VERSION 5.8 ;
BUSBITCHARS "[]" ;
DIVIDERCHAR "/" ;
UNITS
    DATABASE MICRONS 1000 ;
END UNITS

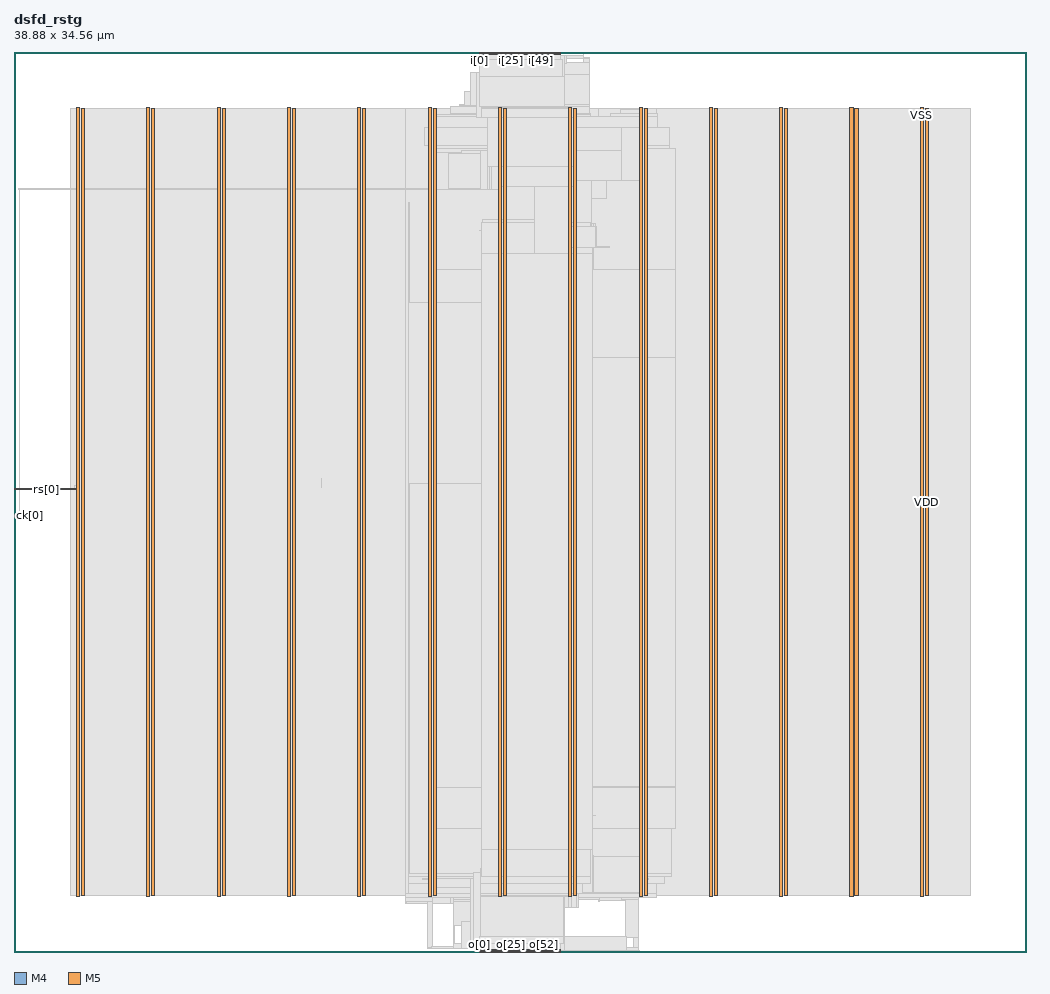
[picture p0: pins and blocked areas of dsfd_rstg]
MACRO dsfd_rstg
  FOREIGN dsfd_rstg 0 0 ;
  CLASS BLOCK ;
  SIZE 38.88 BY 34.56 ;
  PIN ck[0]
    DIRECTION INPUT ;
    USE SIGNAL ;
    PORT
      LAYER M4 ;
        RECT  0 16.752 0.084 16.776 ;
    END
    PORT
      LAYER M4 ;
        RECT  0.06 16.752 0.227 16.776 ;
    END
  END ck[0]
  PIN i[0]
    DIRECTION INPUT ;
    USE SIGNAL ;
    PORT
      LAYER M5 ;
        RECT  17.856 34.476 17.88 34.56 ;
    END
  END i[0]
  PIN i[10]
    DIRECTION INPUT ;
    USE SIGNAL ;
    PORT
      LAYER M5 ;
        RECT  18.336 34.476 18.36 34.56 ;
    END
  END i[10]
  PIN i[11]
    DIRECTION INPUT ;
    USE SIGNAL ;
    PORT
      LAYER M5 ;
        RECT  18.384 34.476 18.408 34.56 ;
    END
  END i[11]
  PIN i[12]
    DIRECTION INPUT ;
    USE SIGNAL ;
    PORT
      LAYER M5 ;
        RECT  18.432 34.476 18.456 34.56 ;
    END
  END i[12]
  PIN i[13]
    DIRECTION INPUT ;
    USE SIGNAL ;
    PORT
      LAYER M5 ;
        RECT  18.48 34.476 18.504 34.56 ;
    END
  END i[13]
  PIN i[14]
    DIRECTION INPUT ;
    USE SIGNAL ;
    PORT
      LAYER M5 ;
        RECT  18.528 34.476 18.552 34.56 ;
    END
  END i[14]
  PIN i[15]
    DIRECTION INPUT ;
    USE SIGNAL ;
    PORT
      LAYER M5 ;
        RECT  18.576 34.476 18.6 34.56 ;
    END
  END i[15]
  PIN i[16]
    DIRECTION INPUT ;
    USE SIGNAL ;
    PORT
      LAYER M5 ;
        RECT  18.624 34.476 18.648 34.56 ;
    END
  END i[16]
  PIN i[17]
    DIRECTION INPUT ;
    USE SIGNAL ;
    PORT
      LAYER M5 ;
        RECT  18.672 34.476 18.696 34.56 ;
    END
  END i[17]
  PIN i[18]
    DIRECTION INPUT ;
    USE SIGNAL ;
    PORT
      LAYER M5 ;
        RECT  18.72 34.476 18.744 34.56 ;
    END
  END i[18]
  PIN i[19]
    DIRECTION INPUT ;
    USE SIGNAL ;
    PORT
      LAYER M5 ;
        RECT  18.768 34.476 18.792 34.56 ;
    END
  END i[19]
  PIN i[1]
    DIRECTION INPUT ;
    USE SIGNAL ;
    PORT
      LAYER M5 ;
        RECT  17.904 34.476 17.928 34.56 ;
    END
  END i[1]
  PIN i[20]
    DIRECTION INPUT ;
    USE SIGNAL ;
    PORT
      LAYER M5 ;
        RECT  18.816 34.476 18.84 34.56 ;
    END
  END i[20]
  PIN i[21]
    DIRECTION INPUT ;
    USE SIGNAL ;
    PORT
      LAYER M5 ;
        RECT  18.864 34.476 18.888 34.56 ;
    END
  END i[21]
  PIN i[22]
    DIRECTION INPUT ;
    USE SIGNAL ;
    PORT
      LAYER M5 ;
        RECT  18.912 34.476 18.936 34.56 ;
    END
  END i[22]
  PIN i[23]
    DIRECTION INPUT ;
    USE SIGNAL ;
    PORT
      LAYER M5 ;
        RECT  18.96 34.476 18.984 34.56 ;
    END
  END i[23]
  PIN i[24]
    DIRECTION INPUT ;
    USE SIGNAL ;
    PORT
      LAYER M5 ;
        RECT  19.008 34.476 19.032 34.56 ;
    END
  END i[24]
  PIN i[25]
    DIRECTION INPUT ;
    USE SIGNAL ;
    PORT
      LAYER M5 ;
        RECT  19.056 34.476 19.08 34.56 ;
    END
  END i[25]
  PIN i[26]
    DIRECTION INPUT ;
    USE SIGNAL ;
    PORT
      LAYER M5 ;
        RECT  19.104 34.476 19.128 34.56 ;
    END
  END i[26]
  PIN i[27]
    DIRECTION INPUT ;
    USE SIGNAL ;
    PORT
      LAYER M5 ;
        RECT  19.152 34.476 19.176 34.56 ;
    END
  END i[27]
  PIN i[28]
    DIRECTION INPUT ;
    USE SIGNAL ;
    PORT
      LAYER M5 ;
        RECT  19.2 34.476 19.224 34.56 ;
    END
  END i[28]
  PIN i[29]
    DIRECTION INPUT ;
    USE SIGNAL ;
    PORT
      LAYER M5 ;
        RECT  19.248 34.476 19.272 34.56 ;
    END
  END i[29]
  PIN i[2]
    DIRECTION INPUT ;
    USE SIGNAL ;
    PORT
      LAYER M5 ;
        RECT  17.952 34.476 17.976 34.56 ;
    END
  END i[2]
  PIN i[30]
    DIRECTION INPUT ;
    USE SIGNAL ;
    PORT
      LAYER M5 ;
        RECT  19.296 34.476 19.32 34.56 ;
    END
  END i[30]
  PIN i[31]
    DIRECTION INPUT ;
    USE SIGNAL ;
    PORT
      LAYER M5 ;
        RECT  19.344 34.476 19.368 34.56 ;
    END
  END i[31]
  PIN i[32]
    DIRECTION INPUT ;
    USE SIGNAL ;
    PORT
      LAYER M5 ;
        RECT  19.392 34.476 19.416 34.56 ;
    END
  END i[32]
  PIN i[33]
    DIRECTION INPUT ;
    USE SIGNAL ;
    PORT
      LAYER M5 ;
        RECT  19.44 34.476 19.464 34.56 ;
    END
  END i[33]
  PIN i[34]
    DIRECTION INPUT ;
    USE SIGNAL ;
    PORT
      LAYER M5 ;
        RECT  19.488 34.476 19.512 34.56 ;
    END
  END i[34]
  PIN i[35]
    DIRECTION INPUT ;
    USE SIGNAL ;
    PORT
      LAYER M5 ;
        RECT  19.536 34.476 19.56 34.56 ;
    END
  END i[35]
  PIN i[36]
    DIRECTION INPUT ;
    USE SIGNAL ;
    PORT
      LAYER M5 ;
        RECT  19.584 34.476 19.608 34.56 ;
    END
  END i[36]
  PIN i[37]
    DIRECTION INPUT ;
    USE SIGNAL ;
    PORT
      LAYER M5 ;
        RECT  19.632 34.476 19.656 34.56 ;
    END
  END i[37]
  PIN i[38]
    DIRECTION INPUT ;
    USE SIGNAL ;
    PORT
      LAYER M5 ;
        RECT  19.68 34.476 19.704 34.56 ;
    END
  END i[38]
  PIN i[39]
    DIRECTION INPUT ;
    USE SIGNAL ;
    PORT
      LAYER M5 ;
        RECT  19.728 34.476 19.752 34.56 ;
    END
  END i[39]
  PIN i[3]
    DIRECTION INPUT ;
    USE SIGNAL ;
    PORT
      LAYER M5 ;
        RECT  18 34.476 18.024 34.56 ;
    END
  END i[3]
  PIN i[40]
    DIRECTION INPUT ;
    USE SIGNAL ;
    PORT
      LAYER M5 ;
        RECT  19.776 34.476 19.8 34.56 ;
    END
  END i[40]
  PIN i[41]
    DIRECTION INPUT ;
    USE SIGNAL ;
    PORT
      LAYER M5 ;
        RECT  19.824 34.476 19.848 34.56 ;
    END
  END i[41]
  PIN i[42]
    DIRECTION INPUT ;
    USE SIGNAL ;
    PORT
      LAYER M5 ;
        RECT  19.872 34.476 19.896 34.56 ;
    END
  END i[42]
  PIN i[43]
    DIRECTION INPUT ;
    USE SIGNAL ;
    PORT
      LAYER M5 ;
        RECT  19.92 34.476 19.944 34.56 ;
    END
  END i[43]
  PIN i[44]
    DIRECTION INPUT ;
    USE SIGNAL ;
    PORT
      LAYER M5 ;
        RECT  19.968 34.476 19.992 34.56 ;
    END
  END i[44]
  PIN i[45]
    DIRECTION INPUT ;
    USE SIGNAL ;
    PORT
      LAYER M5 ;
        RECT  20.016 34.476 20.04 34.56 ;
    END
  END i[45]
  PIN i[46]
    DIRECTION INPUT ;
    USE SIGNAL ;
    PORT
      LAYER M5 ;
        RECT  20.064 34.476 20.088 34.56 ;
    END
  END i[46]
  PIN i[47]
    DIRECTION INPUT ;
    USE SIGNAL ;
    PORT
      LAYER M5 ;
        RECT  20.112 34.476 20.136 34.56 ;
    END
  END i[47]
  PIN i[48]
    DIRECTION INPUT ;
    USE SIGNAL ;
    PORT
      LAYER M5 ;
        RECT  20.16 34.476 20.184 34.56 ;
    END
  END i[48]
  PIN i[49]
    DIRECTION INPUT ;
    USE SIGNAL ;
    PORT
      LAYER M5 ;
        RECT  20.208 34.476 20.232 34.56 ;
    END
  END i[49]
  PIN i[4]
    DIRECTION INPUT ;
    USE SIGNAL ;
    PORT
      LAYER M5 ;
        RECT  18.048 34.476 18.072 34.56 ;
    END
  END i[4]
  PIN i[50]
    DIRECTION INPUT ;
    USE SIGNAL ;
    PORT
      LAYER M5 ;
        RECT  20.256 34.476 20.28 34.56 ;
    END
  END i[50]
  PIN i[51]
    DIRECTION INPUT ;
    USE SIGNAL ;
    PORT
      LAYER M5 ;
        RECT  20.304 34.476 20.328 34.56 ;
    END
  END i[51]
  PIN i[52]
    DIRECTION INPUT ;
    USE SIGNAL ;
    PORT
      LAYER M5 ;
        RECT  20.352 34.476 20.376 34.56 ;
    END
  END i[52]
  PIN i[53]
    DIRECTION INPUT ;
    USE SIGNAL ;
    PORT
      LAYER M5 ;
        RECT  20.4 34.476 20.424 34.56 ;
    END
  END i[53]
  PIN i[54]
    DIRECTION INPUT ;
    USE SIGNAL ;
    PORT
      LAYER M5 ;
        RECT  20.448 34.476 20.472 34.56 ;
    END
  END i[54]
  PIN i[55]
    DIRECTION INPUT ;
    USE SIGNAL ;
    PORT
      LAYER M5 ;
        RECT  20.496 34.476 20.52 34.56 ;
    END
  END i[55]
  PIN i[56]
    DIRECTION INPUT ;
    USE SIGNAL ;
    PORT
      LAYER M5 ;
        RECT  20.544 34.476 20.568 34.56 ;
    END
  END i[56]
  PIN i[57]
    DIRECTION INPUT ;
    USE SIGNAL ;
    PORT
      LAYER M5 ;
        RECT  20.592 34.476 20.616 34.56 ;
    END
  END i[57]
  PIN i[58]
    DIRECTION INPUT ;
    USE SIGNAL ;
    PORT
      LAYER M5 ;
        RECT  20.64 34.476 20.664 34.56 ;
    END
  END i[58]
  PIN i[59]
    DIRECTION INPUT ;
    USE SIGNAL ;
    PORT
      LAYER M5 ;
        RECT  20.688 34.476 20.712 34.56 ;
    END
  END i[59]
  PIN i[5]
    DIRECTION INPUT ;
    USE SIGNAL ;
    PORT
      LAYER M5 ;
        RECT  18.096 34.476 18.12 34.56 ;
    END
  END i[5]
  PIN i[60]
    DIRECTION INPUT ;
    USE SIGNAL ;
    PORT
      LAYER M5 ;
        RECT  20.736 34.476 20.76 34.56 ;
    END
  END i[60]
  PIN i[61]
    DIRECTION INPUT ;
    USE SIGNAL ;
    PORT
      LAYER M5 ;
        RECT  20.784 34.476 20.808 34.56 ;
    END
  END i[61]
  PIN i[62]
    DIRECTION INPUT ;
    USE SIGNAL ;
    PORT
      LAYER M5 ;
        RECT  20.832 34.476 20.856 34.56 ;
    END
  END i[62]
  PIN i[63]
    DIRECTION INPUT ;
    USE SIGNAL ;
    PORT
      LAYER M5 ;
        RECT  20.88 34.476 20.904 34.56 ;
    END
  END i[63]
  PIN i[64]
    DIRECTION INPUT ;
    USE SIGNAL ;
    PORT
      LAYER M5 ;
        RECT  20.928 34.476 20.952 34.56 ;
    END
  END i[64]
  PIN i[65]
    DIRECTION INPUT ;
    USE SIGNAL ;
    PORT
      LAYER M5 ;
        RECT  20.976 34.476 21 34.56 ;
    END
  END i[65]
  PIN i[6]
    DIRECTION INPUT ;
    USE SIGNAL ;
    PORT
      LAYER M5 ;
        RECT  18.144 34.476 18.168 34.56 ;
    END
  END i[6]
  PIN i[7]
    DIRECTION INPUT ;
    USE SIGNAL ;
    PORT
      LAYER M5 ;
        RECT  18.192 34.476 18.216 34.56 ;
    END
  END i[7]
  PIN i[8]
    DIRECTION INPUT ;
    USE SIGNAL ;
    PORT
      LAYER M5 ;
        RECT  18.24 34.476 18.264 34.56 ;
    END
  END i[8]
  PIN i[9]
    DIRECTION INPUT ;
    USE SIGNAL ;
    PORT
      LAYER M5 ;
        RECT  18.288 34.476 18.312 34.56 ;
    END
  END i[9]
  PIN o[0]
    DIRECTION OUTPUT ;
    USE SIGNAL ;
    PORT
      LAYER M5 ;
        RECT  17.856 0 17.88 0.084 ;
    END
  END o[0]
  PIN o[10]
    DIRECTION OUTPUT ;
    USE SIGNAL ;
    PORT
      LAYER M5 ;
        RECT  18.336 0 18.36 0.084 ;
    END
  END o[10]
  PIN o[11]
    DIRECTION OUTPUT ;
    USE SIGNAL ;
    PORT
      LAYER M5 ;
        RECT  18.384 0 18.408 0.084 ;
    END
  END o[11]
  PIN o[12]
    DIRECTION OUTPUT ;
    USE SIGNAL ;
    PORT
      LAYER M5 ;
        RECT  18.432 0 18.456 0.084 ;
    END
  END o[12]
  PIN o[13]
    DIRECTION OUTPUT ;
    USE SIGNAL ;
    PORT
      LAYER M5 ;
        RECT  18.48 0 18.504 0.084 ;
    END
  END o[13]
  PIN o[14]
    DIRECTION OUTPUT ;
    USE SIGNAL ;
    PORT
      LAYER M5 ;
        RECT  18.528 0 18.552 0.084 ;
    END
  END o[14]
  PIN o[15]
    DIRECTION OUTPUT ;
    USE SIGNAL ;
    PORT
      LAYER M5 ;
        RECT  18.576 0 18.6 0.084 ;
    END
  END o[15]
  PIN o[16]
    DIRECTION OUTPUT ;
    USE SIGNAL ;
    PORT
      LAYER M5 ;
        RECT  18.624 0 18.648 0.084 ;
    END
  END o[16]
  PIN o[17]
    DIRECTION OUTPUT ;
    USE SIGNAL ;
    PORT
      LAYER M5 ;
        RECT  18.672 0 18.696 0.084 ;
    END
  END o[17]
  PIN o[18]
    DIRECTION OUTPUT ;
    USE SIGNAL ;
    PORT
      LAYER M5 ;
        RECT  18.72 0 18.744 0.084 ;
    END
  END o[18]
  PIN o[19]
    DIRECTION OUTPUT ;
    USE SIGNAL ;
    PORT
      LAYER M5 ;
        RECT  18.768 0 18.792 0.084 ;
    END
  END o[19]
  PIN o[1]
    DIRECTION OUTPUT ;
    USE SIGNAL ;
    PORT
      LAYER M5 ;
        RECT  17.904 0 17.928 0.084 ;
    END
  END o[1]
  PIN o[20]
    DIRECTION OUTPUT ;
    USE SIGNAL ;
    PORT
      LAYER M5 ;
        RECT  18.816 0 18.84 0.084 ;
    END
  END o[20]
  PIN o[21]
    DIRECTION OUTPUT ;
    USE SIGNAL ;
    PORT
      LAYER M5 ;
        RECT  18.864 0 18.888 0.084 ;
    END
  END o[21]
  PIN o[22]
    DIRECTION OUTPUT ;
    USE SIGNAL ;
    PORT
      LAYER M5 ;
        RECT  18.912 0 18.936 0.084 ;
    END
  END o[22]
  PIN o[23]
    DIRECTION OUTPUT ;
    USE SIGNAL ;
    PORT
      LAYER M5 ;
        RECT  18.96 0 18.984 0.084 ;
    END
  END o[23]
  PIN o[24]
    DIRECTION OUTPUT ;
    USE SIGNAL ;
    PORT
      LAYER M5 ;
        RECT  19.008 0 19.032 0.084 ;
    END
  END o[24]
  PIN o[25]
    DIRECTION OUTPUT ;
    USE SIGNAL ;
    PORT
      LAYER M5 ;
        RECT  19.056 0 19.08 0.084 ;
    END
  END o[25]
  PIN o[26]
    DIRECTION OUTPUT ;
    USE SIGNAL ;
    PORT
      LAYER M5 ;
        RECT  19.104 0 19.128 0.084 ;
    END
  END o[26]
  PIN o[27]
    DIRECTION OUTPUT ;
    USE SIGNAL ;
    PORT
      LAYER M5 ;
        RECT  19.152 0 19.176 0.084 ;
    END
  END o[27]
  PIN o[28]
    DIRECTION OUTPUT ;
    USE SIGNAL ;
    PORT
      LAYER M5 ;
        RECT  19.2 0 19.224 0.084 ;
    END
  END o[28]
  PIN o[29]
    DIRECTION OUTPUT ;
    USE SIGNAL ;
    PORT
      LAYER M5 ;
        RECT  19.248 0 19.272 0.084 ;
    END
  END o[29]
  PIN o[2]
    DIRECTION OUTPUT ;
    USE SIGNAL ;
    PORT
      LAYER M5 ;
        RECT  17.952 0 17.976 0.084 ;
    END
  END o[2]
  PIN o[30]
    DIRECTION OUTPUT ;
    USE SIGNAL ;
    PORT
      LAYER M5 ;
        RECT  19.296 0 19.32 0.084 ;
    END
  END o[30]
  PIN o[31]
    DIRECTION OUTPUT ;
    USE SIGNAL ;
    PORT
      LAYER M5 ;
        RECT  19.344 0 19.368 0.084 ;
    END
  END o[31]
  PIN o[32]
    DIRECTION OUTPUT ;
    USE SIGNAL ;
    PORT
      LAYER M5 ;
        RECT  19.392 0 19.416 0.084 ;
    END
  END o[32]
  PIN o[33]
    DIRECTION OUTPUT ;
    USE SIGNAL ;
    PORT
      LAYER M5 ;
        RECT  19.44 0 19.464 0.084 ;
    END
  END o[33]
  PIN o[34]
    DIRECTION OUTPUT ;
    USE SIGNAL ;
    PORT
      LAYER M5 ;
        RECT  19.488 0 19.512 0.084 ;
    END
  END o[34]
  PIN o[35]
    DIRECTION OUTPUT ;
    USE SIGNAL ;
    PORT
      LAYER M5 ;
        RECT  19.536 0 19.56 0.084 ;
    END
  END o[35]
  PIN o[36]
    DIRECTION OUTPUT ;
    USE SIGNAL ;
    PORT
      LAYER M5 ;
        RECT  19.584 0 19.608 0.084 ;
    END
  END o[36]
  PIN o[37]
    DIRECTION OUTPUT ;
    USE SIGNAL ;
    PORT
      LAYER M5 ;
        RECT  19.632 0 19.656 0.084 ;
    END
  END o[37]
  PIN o[38]
    DIRECTION OUTPUT ;
    USE SIGNAL ;
    PORT
      LAYER M5 ;
        RECT  19.68 0 19.704 0.084 ;
    END
  END o[38]
  PIN o[39]
    DIRECTION OUTPUT ;
    USE SIGNAL ;
    PORT
      LAYER M5 ;
        RECT  19.728 0 19.752 0.084 ;
    END
  END o[39]
  PIN o[3]
    DIRECTION OUTPUT ;
    USE SIGNAL ;
    PORT
      LAYER M5 ;
        RECT  18 0 18.024 0.084 ;
    END
  END o[3]
  PIN o[40]
    DIRECTION OUTPUT ;
    USE SIGNAL ;
    PORT
      LAYER M5 ;
        RECT  19.776 0 19.8 0.084 ;
    END
  END o[40]
  PIN o[41]
    DIRECTION OUTPUT ;
    USE SIGNAL ;
    PORT
      LAYER M5 ;
        RECT  19.824 0 19.848 0.084 ;
    END
  END o[41]
  PIN o[42]
    DIRECTION OUTPUT ;
    USE SIGNAL ;
    PORT
      LAYER M5 ;
        RECT  19.872 0 19.896 0.084 ;
    END
  END o[42]
  PIN o[43]
    DIRECTION OUTPUT ;
    USE SIGNAL ;
    PORT
      LAYER M5 ;
        RECT  19.92 0 19.944 0.084 ;
    END
  END o[43]
  PIN o[44]
    DIRECTION OUTPUT ;
    USE SIGNAL ;
    PORT
      LAYER M5 ;
        RECT  19.968 0 19.992 0.084 ;
    END
  END o[44]
  PIN o[45]
    DIRECTION OUTPUT ;
    USE SIGNAL ;
    PORT
      LAYER M5 ;
        RECT  20.016 0 20.04 0.084 ;
    END
  END o[45]
  PIN o[46]
    DIRECTION OUTPUT ;
    USE SIGNAL ;
    PORT
      LAYER M5 ;
        RECT  20.064 0 20.088 0.084 ;
    END
  END o[46]
  PIN o[47]
    DIRECTION OUTPUT ;
    USE SIGNAL ;
    PORT
      LAYER M5 ;
        RECT  20.112 0 20.136 0.084 ;
    END
  END o[47]
  PIN o[48]
    DIRECTION OUTPUT ;
    USE SIGNAL ;
    PORT
      LAYER M5 ;
        RECT  20.16 0 20.184 0.084 ;
    END
  END o[48]
  PIN o[49]
    DIRECTION OUTPUT ;
    USE SIGNAL ;
    PORT
      LAYER M5 ;
        RECT  20.208 0 20.232 0.084 ;
    END
  END o[49]
  PIN o[4]
    DIRECTION OUTPUT ;
    USE SIGNAL ;
    PORT
      LAYER M5 ;
        RECT  18.048 0 18.072 0.084 ;
    END
  END o[4]
  PIN o[50]
    DIRECTION OUTPUT ;
    USE SIGNAL ;
    PORT
      LAYER M5 ;
        RECT  20.256 0 20.28 0.084 ;
    END
  END o[50]
  PIN o[51]
    DIRECTION OUTPUT ;
    USE SIGNAL ;
    PORT
      LAYER M5 ;
        RECT  20.304 0 20.328 0.084 ;
    END
  END o[51]
  PIN o[52]
    DIRECTION OUTPUT ;
    USE SIGNAL ;
    PORT
      LAYER M5 ;
        RECT  20.352 0 20.376 0.084 ;
    END
  END o[52]
  PIN o[53]
    DIRECTION OUTPUT ;
    USE SIGNAL ;
    PORT
      LAYER M5 ;
        RECT  20.4 0 20.424 0.084 ;
    END
  END o[53]
  PIN o[54]
    DIRECTION OUTPUT ;
    USE SIGNAL ;
    PORT
      LAYER M5 ;
        RECT  20.448 0 20.472 0.084 ;
    END
  END o[54]
  PIN o[55]
    DIRECTION OUTPUT ;
    USE SIGNAL ;
    PORT
      LAYER M5 ;
        RECT  20.496 0 20.52 0.084 ;
    END
  END o[55]
  PIN o[56]
    DIRECTION OUTPUT ;
    USE SIGNAL ;
    PORT
      LAYER M5 ;
        RECT  20.544 0 20.568 0.084 ;
    END
  END o[56]
  PIN o[57]
    DIRECTION OUTPUT ;
    USE SIGNAL ;
    PORT
      LAYER M5 ;
        RECT  20.592 0 20.616 0.084 ;
    END
  END o[57]
  PIN o[58]
    DIRECTION OUTPUT ;
    USE SIGNAL ;
    PORT
      LAYER M5 ;
        RECT  20.64 0 20.664 0.084 ;
    END
  END o[58]
  PIN o[59]
    DIRECTION OUTPUT ;
    USE SIGNAL ;
    PORT
      LAYER M5 ;
        RECT  20.688 0 20.712 0.084 ;
    END
  END o[59]
  PIN o[5]
    DIRECTION OUTPUT ;
    USE SIGNAL ;
    PORT
      LAYER M5 ;
        RECT  18.096 0 18.12 0.084 ;
    END
  END o[5]
  PIN o[60]
    DIRECTION OUTPUT ;
    USE SIGNAL ;
    PORT
      LAYER M5 ;
        RECT  20.736 0 20.76 0.084 ;
    END
  END o[60]
  PIN o[61]
    DIRECTION OUTPUT ;
    USE SIGNAL ;
    PORT
      LAYER M5 ;
        RECT  20.784 0 20.808 0.084 ;
    END
  END o[61]
  PIN o[62]
    DIRECTION OUTPUT ;
    USE SIGNAL ;
    PORT
      LAYER M5 ;
        RECT  20.832 0 20.856 0.084 ;
    END
  END o[62]
  PIN o[63]
    DIRECTION OUTPUT ;
    USE SIGNAL ;
    PORT
      LAYER M5 ;
        RECT  20.88 0 20.904 0.084 ;
    END
  END o[63]
  PIN o[64]
    DIRECTION OUTPUT ;
    USE SIGNAL ;
    PORT
      LAYER M5 ;
        RECT  20.928 0 20.952 0.084 ;
    END
  END o[64]
  PIN o[65]
    DIRECTION OUTPUT ;
    USE SIGNAL ;
    PORT
      LAYER M5 ;
        RECT  20.976 0 21 0.084 ;
    END
  END o[65]
  PIN o[6]
    DIRECTION OUTPUT ;
    USE SIGNAL ;
    PORT
      LAYER M5 ;
        RECT  18.144 0 18.168 0.084 ;
    END
  END o[6]
  PIN o[7]
    DIRECTION OUTPUT ;
    USE SIGNAL ;
    PORT
      LAYER M5 ;
        RECT  18.192 0 18.216 0.084 ;
    END
  END o[7]
  PIN o[8]
    DIRECTION OUTPUT ;
    USE SIGNAL ;
    PORT
      LAYER M5 ;
        RECT  18.24 0 18.264 0.084 ;
    END
  END o[8]
  PIN o[9]
    DIRECTION OUTPUT ;
    USE SIGNAL ;
    PORT
      LAYER M5 ;
        RECT  18.288 0 18.312 0.084 ;
    END
  END o[9]
  PIN rs[0]
    DIRECTION INPUT ;
    USE SIGNAL ;
    PORT
      LAYER M4 ;
        RECT  0 17.76 0.084 17.784 ;
    END
    PORT
      LAYER M4 ;
        RECT  0.06 17.76 2.408 17.784 ;
    END
  END rs[0]
  PIN VDD
    DIRECTION INOUT ;
    USE POWER ;
    PORT
      LAYER M5 ;
        RECT  34.992 2.151 35.112 32.409 ;
        RECT  32.292 2.151 32.412 32.409 ;
        RECT  29.592 2.151 29.712 32.409 ;
        RECT  26.892 2.151 27.012 32.409 ;
        RECT  24.192 2.151 24.312 32.409 ;
        RECT  21.492 2.151 21.612 32.409 ;
        RECT  18.792 2.151 18.912 32.409 ;
        RECT  16.092 2.151 16.212 32.409 ;
        RECT  13.392 2.151 13.512 32.409 ;
        RECT  10.692 2.151 10.812 32.409 ;
        RECT  7.992 2.151 8.112 32.409 ;
        RECT  5.292 2.151 5.412 32.409 ;
        RECT  2.592 2.151 2.712 32.409 ;
    END
  END VDD
  PIN VSS
    DIRECTION INOUT ;
    USE GROUND ;
    PORT
      LAYER M5 ;
        RECT  34.8 2.137 34.92 32.423 ;
        RECT  32.1 2.137 32.22 32.423 ;
        RECT  29.4 2.137 29.52 32.423 ;
        RECT  26.7 2.137 26.82 32.423 ;
        RECT  24 2.137 24.12 32.423 ;
        RECT  21.3 2.137 21.42 32.423 ;
        RECT  18.6 2.137 18.72 32.423 ;
        RECT  15.9 2.137 16.02 32.423 ;
        RECT  13.2 2.137 13.32 32.423 ;
        RECT  10.5 2.137 10.62 32.423 ;
        RECT  7.8 2.137 7.92 32.423 ;
        RECT  5.1 2.137 5.22 32.423 ;
        RECT  2.4 2.137 2.52 32.423 ;
    END
  END VSS
  # OT_OBS_CLOSED layer=M5 d_um=1.536 added=1
  OBS
    LAYER RVTN ;
     RECT  2.16 2.16 36.72 2.295 ;
     RECT  2.16 2.565 36.72 2.835 ;
     RECT  2.16 3.105 36.72 3.375 ;
     RECT  2.16 3.645 36.72 3.915 ;
     RECT  2.16 4.185 36.72 4.455 ;
     RECT  2.16 4.725 36.72 4.995 ;
     RECT  2.16 5.265 36.72 5.535 ;
     RECT  2.16 5.805 36.72 6.075 ;
     RECT  2.16 6.345 36.72 6.615 ;
     RECT  2.16 6.885 36.72 7.155 ;
     RECT  2.16 7.425 36.72 7.695 ;
     RECT  2.16 7.965 36.72 8.235 ;
     RECT  2.16 8.505 36.72 8.775 ;
     RECT  2.16 9.045 36.72 9.315 ;
     RECT  2.16 9.585 36.72 9.855 ;
     RECT  2.16 10.125 36.72 10.395 ;
     RECT  2.16 10.665 36.72 10.935 ;
     RECT  2.16 11.205 36.72 11.475 ;
     RECT  2.16 11.745 36.72 12.015 ;
     RECT  2.16 12.285 36.72 12.555 ;
     RECT  2.16 12.825 36.72 13.095 ;
     RECT  2.16 13.365 36.72 13.635 ;
     RECT  2.16 13.905 36.72 14.175 ;
     RECT  2.16 14.445 36.72 14.715 ;
     RECT  2.16 14.985 36.72 15.255 ;
     RECT  2.16 15.525 36.72 15.795 ;
     RECT  2.16 16.065 36.72 16.335 ;
     RECT  2.16 16.605 36.72 16.875 ;
     RECT  2.16 17.145 36.72 17.415 ;
     RECT  2.16 17.685 36.72 17.955 ;
     RECT  2.16 18.225 36.72 18.495 ;
     RECT  2.16 18.765 36.72 19.035 ;
     RECT  2.16 19.305 36.72 19.575 ;
     RECT  2.16 19.845 36.72 20.115 ;
     RECT  2.16 20.385 36.72 20.655 ;
     RECT  2.16 20.925 36.72 21.195 ;
     RECT  2.16 21.465 36.72 21.735 ;
     RECT  2.16 22.005 36.72 22.275 ;
     RECT  2.16 22.545 36.72 22.815 ;
     RECT  2.16 23.085 36.72 23.355 ;
     RECT  2.16 23.625 36.72 23.895 ;
     RECT  2.16 24.165 36.72 24.435 ;
     RECT  2.16 24.705 36.72 24.975 ;
     RECT  2.16 25.245 36.72 25.515 ;
     RECT  2.16 25.785 36.72 26.055 ;
     RECT  2.16 26.325 36.72 26.595 ;
     RECT  2.16 26.865 36.72 27.135 ;
     RECT  2.16 27.405 36.72 27.675 ;
     RECT  2.16 27.945 36.72 28.215 ;
     RECT  2.16 28.485 36.72 28.755 ;
     RECT  2.16 29.025 36.72 29.295 ;
     RECT  2.16 29.565 36.72 29.835 ;
     RECT  2.16 30.105 36.72 30.375 ;
     RECT  2.16 30.645 36.72 30.915 ;
     RECT  2.16 31.185 36.72 31.455 ;
     RECT  2.16 31.725 36.72 31.995 ;
     RECT  2.16 32.265 36.72 32.4 ;
    LAYER RVTP ;
     RECT  2.16 2.295 36.72 2.565 ;
     RECT  2.16 2.835 36.72 3.105 ;
     RECT  2.16 3.375 36.72 3.645 ;
     RECT  2.16 3.915 36.72 4.185 ;
     RECT  2.16 4.455 36.72 4.725 ;
     RECT  2.16 4.995 36.72 5.265 ;
     RECT  2.16 5.535 36.72 5.805 ;
     RECT  2.16 6.075 36.72 6.345 ;
     RECT  2.16 6.615 36.72 6.885 ;
     RECT  2.16 7.155 36.72 7.425 ;
     RECT  2.16 7.695 36.72 7.965 ;
     RECT  2.16 8.235 36.72 8.505 ;
     RECT  2.16 8.775 36.72 9.045 ;
     RECT  2.16 9.315 36.72 9.585 ;
     RECT  2.16 9.855 36.72 10.125 ;
     RECT  2.16 10.395 36.72 10.665 ;
     RECT  2.16 10.935 36.72 11.205 ;
     RECT  2.16 11.475 36.72 11.745 ;
     RECT  2.16 12.015 36.72 12.285 ;
     RECT  2.16 12.555 36.72 12.825 ;
     RECT  2.16 13.095 36.72 13.365 ;
     RECT  2.16 13.635 36.72 13.905 ;
     RECT  2.16 14.175 36.72 14.445 ;
     RECT  2.16 14.715 36.72 14.985 ;
     RECT  2.16 15.255 36.72 15.525 ;
     RECT  2.16 15.795 36.72 16.065 ;
     RECT  2.16 16.335 36.72 16.605 ;
     RECT  2.16 16.875 36.72 17.145 ;
     RECT  2.16 17.415 36.72 17.685 ;
     RECT  2.16 17.955 36.72 18.225 ;
     RECT  2.16 18.495 36.72 18.765 ;
     RECT  2.16 19.035 36.72 19.305 ;
     RECT  2.16 19.575 36.72 19.845 ;
     RECT  2.16 20.115 36.72 20.385 ;
     RECT  2.16 20.655 36.72 20.925 ;
     RECT  2.16 21.195 36.72 21.465 ;
     RECT  2.16 21.735 36.72 22.005 ;
     RECT  2.16 22.275 36.72 22.545 ;
     RECT  2.16 22.815 36.72 23.085 ;
     RECT  2.16 23.355 36.72 23.625 ;
     RECT  2.16 23.895 36.72 24.165 ;
     RECT  2.16 24.435 36.72 24.705 ;
     RECT  2.16 24.975 36.72 25.245 ;
     RECT  2.16 25.515 36.72 25.785 ;
     RECT  2.16 26.055 36.72 26.325 ;
     RECT  2.16 26.595 36.72 26.865 ;
     RECT  2.16 27.135 36.72 27.405 ;
     RECT  2.16 27.675 36.72 27.945 ;
     RECT  2.16 28.215 36.72 28.485 ;
     RECT  2.16 28.755 36.72 29.025 ;
     RECT  2.16 29.295 36.72 29.565 ;
     RECT  2.16 29.835 36.72 30.105 ;
     RECT  2.16 30.375 36.72 30.645 ;
     RECT  2.16 30.915 36.72 31.185 ;
     RECT  2.16 31.455 36.72 31.725 ;
     RECT  2.16 31.995 36.72 32.265 ;
    LAYER M1 ;
     RECT  2.16 2.151 36.72 32.409 ;
    LAYER M2 ;
     RECT  2.16 2.151 15.043 32.409 ;
     RECT  15.043 1.881 16.771 32.409 ;
     RECT  16.771 1.881 18.031 32.454 ;
     RECT  18.031 1.881 18.095 33.066 ;
     RECT  18.095 1.926 18.239 33.066 ;
     RECT  18.239 1.926 19.427 32.409 ;
     RECT  20.803 1.152 21.011 1.17 ;
     RECT  19.427 2.151 21.739 32.409 ;
     RECT  21.739 2.034 22.459 32.409 ;
     RECT  22.459 1.962 23.855 32.409 ;
     RECT  23.855 2.106 24.683 32.409 ;
     RECT  24.683 2.151 36.72 32.409 ;
    LAYER M3 ;
     RECT  19.476 0.043 19.494 0.091 ;
     RECT  23.976 0.043 23.994 0.091 ;
     RECT  18.144 0.091 18.162 0.139 ;
     RECT  15.876 0.139 15.894 0.187 ;
     RECT  18.144 0.139 18.666 0.187 ;
     RECT  19.476 0.091 19.71 0.187 ;
     RECT  20.844 0.139 20.97 0.187 ;
     RECT  19.476 0.187 21.042 0.221 ;
     RECT  18.108 0.187 18.666 0.523 ;
     RECT  18.108 0.523 18.99 0.571 ;
     RECT  23.796 0.091 23.994 0.571 ;
     RECT  16.884 0.283 16.902 1.003 ;
     RECT  17.64 0.571 18.99 1.003 ;
     RECT  20.088 0.221 21.042 1.147 ;
     RECT  20.088 1.147 21.114 1.723 ;
     RECT  20.088 1.723 21.654 1.771 ;
     RECT  15.048 1.876 15.066 1.921 ;
     RECT  15.876 0.187 16.074 1.921 ;
     RECT  16.884 1.003 18.99 1.921 ;
     RECT  19.764 1.771 21.654 1.921 ;
     RECT  16.884 1.921 21.654 2.029 ;
     RECT  22.464 1.957 22.482 2.029 ;
     RECT  23.472 0.571 23.994 2.029 ;
     RECT  15.048 1.921 16.074 2.101 ;
     RECT  16.884 2.029 22.482 2.101 ;
     RECT  23.328 2.029 23.994 2.101 ;
     RECT  15.048 2.101 24.678 2.255 ;
     RECT  2.415 2.143 2.505 2.413 ;
     RECT  5.115 2.143 5.205 2.413 ;
     RECT  7.815 2.143 7.905 2.413 ;
     RECT  10.515 2.143 10.605 2.413 ;
     RECT  13.215 2.143 13.305 2.413 ;
     RECT  26.715 2.143 26.805 2.413 ;
     RECT  29.415 2.143 29.505 2.413 ;
     RECT  32.115 2.143 32.205 2.413 ;
     RECT  34.815 2.143 34.905 2.413 ;
     RECT  15.156 2.255 24.678 2.641 ;
     RECT  15.156 2.641 24.966 2.911 ;
     RECT  15.156 2.911 25.254 3.029 ;
     RECT  15.915 3.029 25.254 4.729 ;
     RECT  15.915 4.729 25.398 6.305 ;
     RECT  20.196 6.305 25.398 6.341 ;
     RECT  2.415 2.413 2.697 17.755 ;
     RECT  2.304 17.755 2.697 17.915 ;
     RECT  15.156 3.029 15.174 17.995 ;
     RECT  15.915 6.305 19.134 17.995 ;
     RECT  11.808 17.851 11.826 18.185 ;
     RECT  20.484 6.341 25.398 22.819 ;
     RECT  15.156 17.995 19.134 24.935 ;
     RECT  15.915 24.935 19.134 26.203 ;
     RECT  20.376 22.819 25.398 26.203 ;
     RECT  15.156 24.935 15.174 28.787 ;
     RECT  15.915 26.203 25.398 30.839 ;
     RECT  15.915 30.839 25.182 30.955 ;
     RECT  15.768 30.955 25.182 31.649 ;
     RECT  15.915 31.649 24.714 32.099 ;
     RECT  2.415 17.915 2.697 32.147 ;
     RECT  5.115 2.413 5.397 32.147 ;
     RECT  7.815 2.413 8.097 32.147 ;
     RECT  10.515 2.413 10.797 32.147 ;
     RECT  13.215 2.413 13.497 32.147 ;
     RECT  15.915 32.099 22.122 32.147 ;
     RECT  26.715 2.413 26.997 32.147 ;
     RECT  29.415 2.413 29.697 32.147 ;
     RECT  32.115 2.413 32.397 32.147 ;
     RECT  34.815 2.413 35.097 32.147 ;
     RECT  16.776 32.147 22.122 32.189 ;
     RECT  22.896 32.099 24.714 32.189 ;
     RECT  23.292 32.189 24.105 32.369 ;
     RECT  2.415 32.147 2.505 32.417 ;
     RECT  5.115 32.147 5.205 32.417 ;
     RECT  7.815 32.147 7.905 32.417 ;
     RECT  10.515 32.147 10.605 32.417 ;
     RECT  13.215 32.147 13.305 32.417 ;
     RECT  15.915 32.147 16.005 32.417 ;
     RECT  24.015 32.369 24.105 32.417 ;
     RECT  26.715 32.147 26.805 32.417 ;
     RECT  29.415 32.147 29.505 32.417 ;
     RECT  32.115 32.147 32.205 32.417 ;
     RECT  34.815 32.147 34.905 32.417 ;
     RECT  16.776 32.189 22.086 32.459 ;
     RECT  17.1 32.459 22.086 32.525 ;
     RECT  17.316 32.525 18.774 33.053 ;
     RECT  17.532 33.053 18.594 33.101 ;
     RECT  19.62 32.525 22.086 33.677 ;
     RECT  17.532 33.101 18.342 33.773 ;
     RECT  19.944 33.677 22.086 34.157 ;
     RECT  19.944 34.157 21.114 34.205 ;
     RECT  18 33.773 18.342 34.349 ;
     RECT  19.944 34.205 20.286 34.349 ;
     RECT  21.852 34.157 22.086 34.349 ;
     RECT  18 34.349 18.018 34.397 ;
     RECT  19.944 34.349 20.142 34.397 ;
     RECT  21.096 34.205 21.114 34.397 ;
     RECT  20.124 34.397 20.142 34.445 ;
     RECT  21.852 34.349 21.87 34.445 ;
    LAYER M4 ;
     RECT  0.181 29.28 2.408 29.304 ;
     RECT  2.408 2.148 2.512 32.412 ;
     RECT  2.512 2.418 2.704 32.142 ;
     RECT  2.704 29.28 5.108 29.304 ;
     RECT  5.108 2.148 5.212 32.412 ;
     RECT  5.212 2.418 5.404 32.142 ;
     RECT  5.404 29.28 7.808 29.304 ;
     RECT  7.808 2.148 7.912 32.412 ;
     RECT  7.912 2.418 8.104 32.142 ;
     RECT  8.104 29.28 10.508 29.304 ;
     RECT  10.508 2.148 10.612 32.412 ;
     RECT  10.612 2.418 10.804 32.142 ;
     RECT  10.804 29.28 13.208 29.304 ;
     RECT  13.208 2.148 13.312 32.412 ;
     RECT  13.312 2.418 13.504 32.142 ;
     RECT  15.685 2.784 15.908 2.808 ;
     RECT  13.504 29.28 15.908 29.304 ;
     RECT  15.757 30.96 15.908 30.984 ;
     RECT  15.908 2.148 16.012 32.412 ;
     RECT  15.865 0.144 16.045 0.168 ;
     RECT  16.012 2.418 16.204 32.142 ;
     RECT  16.204 29.28 16.697 30.696 ;
     RECT  16.045 0.144 16.873 0.216 ;
     RECT  16.873 0.144 17.197 0.312 ;
     RECT  16.697 30.672 17.197 30.696 ;
     RECT  17.089 32.496 17.305 32.52 ;
     RECT  17.197 0.144 17.521 1.176 ;
     RECT  16.204 2.496 17.521 2.808 ;
     RECT  17.305 32.496 17.521 33.048 ;
     RECT  17.521 0.144 17.629 2.808 ;
     RECT  17.521 32.496 17.773 33.768 ;
     RECT  17.629 0.144 17.9 3.048 ;
     RECT  16.697 29.28 17.917 29.304 ;
     RECT  17.197 30.672 17.917 30.792 ;
     RECT  17.881 27.696 17.941 27.72 ;
     RECT  17.941 27.696 17.989 28.008 ;
     RECT  17.773 32.064 17.989 33.768 ;
     RECT  17.9 0.144 18.133 3.192 ;
     RECT  17.989 27.696 18.181 28.104 ;
     RECT  17.917 29.28 18.181 30.792 ;
     RECT  17.989 32.064 18.181 34.392 ;
     RECT  18.133 0.096 18.241 3.192 ;
     RECT  18.241 0.096 18.275 3.624 ;
     RECT  18.181 29.28 18.275 34.392 ;
     RECT  18.229 5.232 18.277 5.256 ;
     RECT  18.275 29.28 18.353 34.344 ;
     RECT  18.277 5.136 18.469 5.256 ;
     RECT  18.275 0.144 18.565 3.624 ;
     RECT  18.469 4.992 18.565 5.256 ;
     RECT  18.565 0.144 18.608 5.256 ;
     RECT  18.181 27.6 18.608 28.104 ;
     RECT  18.353 29.28 18.608 34.296 ;
     RECT  18.608 0.144 18.904 34.296 ;
     RECT  18.904 29.088 18.947 34.296 ;
     RECT  18.947 29.088 18.965 32.52 ;
     RECT  18.965 29.088 19.225 31.944 ;
     RECT  18.904 0.144 19.289 5.832 ;
     RECT  18.947 33.6 19.381 34.296 ;
     RECT  19.289 0.144 19.465 5.784 ;
     RECT  19.381 33.6 19.621 34.344 ;
     RECT  19.465 0.048 19.693 5.784 ;
     RECT  19.621 33.6 19.861 34.392 ;
     RECT  19.693 0.048 19.865 5.736 ;
     RECT  18.904 26.208 19.916 27.912 ;
     RECT  19.225 29.088 19.916 30.792 ;
     RECT  19.865 0.048 19.955 5.256 ;
     RECT  19.916 26.208 20.003 30.792 ;
     RECT  19.225 31.92 20.101 31.944 ;
     RECT  20.003 29.04 20.197 30.792 ;
     RECT  20.101 31.92 20.197 32.088 ;
     RECT  20.197 29.04 20.581 32.088 ;
     RECT  20.581 29.04 20.821 32.136 ;
     RECT  20.003 26.208 20.869 27.336 ;
     RECT  19.955 0.048 21.125 5.208 ;
     RECT  19.861 33.6 21.155 34.44 ;
     RECT  21.155 34.128 21.233 34.44 ;
     RECT  21.125 1.728 21.308 5.208 ;
     RECT  20.761 14.208 21.308 14.232 ;
     RECT  20.869 25.68 21.308 27.336 ;
     RECT  20.821 29.04 21.308 32.28 ;
     RECT  21.308 1.728 21.412 32.412 ;
     RECT  21.412 1.728 21.604 32.142 ;
     RECT  21.604 1.728 21.665 5.256 ;
     RECT  21.665 2.256 21.827 4.248 ;
     RECT  21.233 34.32 21.881 34.44 ;
     RECT  21.881 34.32 22.097 34.344 ;
     RECT  21.604 26.208 22.169 29.64 ;
     RECT  21.827 2.304 22.205 4.248 ;
     RECT  22.205 2.304 22.211 3.96 ;
     RECT  22.211 2.304 22.241 3.72 ;
     RECT  22.169 26.208 22.249 27.96 ;
     RECT  21.665 5.232 22.313 5.256 ;
     RECT  22.249 27.072 22.313 27.96 ;
     RECT  22.313 27.072 22.355 27.864 ;
     RECT  22.355 27.072 22.385 27.192 ;
     RECT  22.169 28.944 22.745 29.64 ;
     RECT  22.385 27.072 22.853 27.096 ;
     RECT  22.745 29.616 23.317 29.64 ;
     RECT  21.604 30.768 23.317 31.656 ;
     RECT  21.125 0.048 23.501 0.6 ;
     RECT  23.501 0.048 23.969 0.168 ;
     RECT  23.969 0.048 24.005 0.072 ;
     RECT  22.241 2.304 24.008 3.672 ;
     RECT  23.317 29.616 24.008 31.656 ;
     RECT  24.008 2.148 24.112 32.412 ;
     RECT  24.112 2.418 24.304 32.142 ;
     RECT  24.304 2.784 24.365 2.808 ;
     RECT  26.708 2.148 26.812 32.412 ;
     RECT  26.812 2.418 27.004 32.142 ;
     RECT  29.408 2.148 29.512 32.412 ;
     RECT  29.512 2.418 29.704 32.142 ;
     RECT  32.108 2.148 32.212 32.412 ;
     RECT  32.212 2.418 32.404 32.142 ;
     RECT  34.808 2.148 34.912 32.412 ;
     RECT  34.912 2.418 35.104 32.142 ;
    LAYER M5 ;
     RECT  17.856 0.016 21 0.325 ;
     RECT  17.856 0.325 21.096 0.611 ;
     RECT  17.904 0.611 21.096 2.137 ;
     RECT  2.4 2.137 2.52 2.151 ;
     RECT  5.1 2.137 5.22 2.151 ;
     RECT  7.8 2.137 7.92 2.151 ;
     RECT  10.5 2.137 10.62 2.151 ;
     RECT  13.2 2.137 13.32 2.151 ;
     RECT  15.9 2.137 16.02 2.151 ;
     RECT  17.904 2.137 21.42 2.151 ;
     RECT  24 2.137 24.12 2.151 ;
     RECT  26.7 2.137 26.82 2.151 ;
     RECT  29.4 2.137 29.52 2.151 ;
     RECT  32.1 2.137 32.22 2.151 ;
     RECT  34.8 2.137 34.92 2.151 ;
     RECT  17.904 2.151 21.612 2.245 ;
     RECT  17.904 2.245 21.816 2.629 ;
     RECT  17.904 2.629 22.152 2.915 ;
     RECT  17.952 2.915 22.152 3.925 ;
     RECT  17.952 3.925 22.2 26.819 ;
     RECT  21.3 26.819 22.2 27.061 ;
     RECT  21.3 27.061 22.344 27.875 ;
     RECT  17.952 26.819 19.992 28.019 ;
     RECT  21.3 27.875 22.152 28.019 ;
     RECT  18 28.019 19.992 28.115 ;
     RECT  0.192 16.741 0.216 29.315 ;
     RECT  18.6 28.115 19.992 29.413 ;
     RECT  21.3 28.019 21.612 29.413 ;
     RECT  18.6 29.413 21.612 30.181 ;
     RECT  18.192 30.181 21.612 32.053 ;
     RECT  2.4 2.151 2.712 32.409 ;
     RECT  5.1 2.151 5.412 32.409 ;
     RECT  7.8 2.151 8.112 32.409 ;
     RECT  10.5 2.151 10.812 32.409 ;
     RECT  13.2 2.151 13.512 32.409 ;
     RECT  15.9 2.151 16.212 32.409 ;
     RECT  17.952 32.053 21.612 32.409 ;
     RECT  24 2.151 24.312 32.409 ;
     RECT  26.7 2.151 27.012 32.409 ;
     RECT  29.4 2.151 29.712 32.409 ;
     RECT  32.1 2.151 32.412 32.409 ;
     RECT  34.8 2.151 35.112 32.409 ;
     RECT  2.4 32.409 2.52 32.423 ;
     RECT  5.1 32.409 5.22 32.423 ;
     RECT  7.8 32.409 7.92 32.423 ;
     RECT  10.5 32.409 10.62 32.423 ;
     RECT  13.2 32.409 13.32 32.423 ;
     RECT  15.9 32.409 16.02 32.423 ;
     RECT  17.952 32.409 21.42 32.423 ;
     RECT  24 32.409 24.12 32.423 ;
     RECT  26.7 32.409 26.82 32.423 ;
     RECT  29.4 32.409 29.52 32.423 ;
     RECT  32.1 32.409 32.22 32.423 ;
     RECT  34.8 32.409 34.92 32.423 ;
     RECT  17.952 32.423 21.144 32.485 ;
     RECT  17.856 32.485 21.144 33.635 ;
     RECT  17.856 33.635 21.048 34.259 ;
     RECT  17.856 34.259 21 34.512 ;
     RECT  19.992 26.819 21.3 29.413 ;
  END
END dsfd_rstg
END LIBRARY
